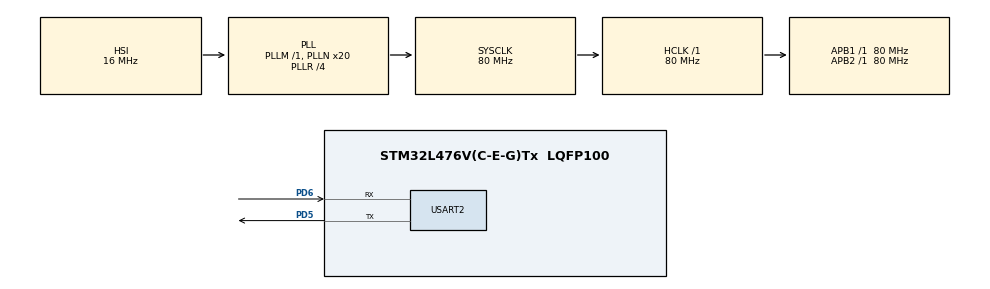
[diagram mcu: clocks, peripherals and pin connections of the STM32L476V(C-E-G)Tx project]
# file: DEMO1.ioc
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Mcu.Family=STM32L4
Mcu.Name=STM32L476V(C-E-G)Tx
Mcu.Package=LQFP100
NVIC.PriorityGroup=NVIC_PRIORITYGROUP_4
PD5.Mode=Asynchronous
PD5.Signal=USART2_TX
PD6.Mode=Asynchronous
PD6.Signal=USART2_RX
PH0-OSC_IN\ (PH0).Mode=HSE-External-Oscillator
PH0-OSC_IN\ (PH0).Signal=RCC_OSC_IN
PH1-OSC_OUT\ (PH1).Mode=HSE-External-Oscillator
PH1-OSC_OUT\ (PH1).Signal=RCC_OSC_OUT
ProjectManager.HeapSize=0x200
ProjectManager.StackSize=0x400
ProjectManager.TargetToolchain=SW4STM32
RCC.ADCFreq_Value=64000000
RCC.AHBFreq_Value=80000000
RCC.APB1Freq_Value=80000000
RCC.APB1TimFreq_Value=80000000
RCC.APB2Freq_Value=80000000
RCC.APB2TimFreq_Value=80000000
RCC.CortexFreq_Value=80000000
RCC.HCLKFreq_Value=80000000
RCC.HSE_VALUE=48000000
RCC.HSI_VALUE=16000000
RCC.LSE_VALUE=32768
RCC.MSI_VALUE=4000000
RCC.PLLN=20
RCC.PLLR=RCC_PLLR_DIV4
RCC.PLLSourceVirtual=RCC_PLLSOURCE_HSI
RCC.SYSCLKFreq_VALUE=80000000
RCC.SYSCLKSource=RCC_SYSCLKSOURCE_PLLCLK
RCC.USBFreq_Value=64000000
RCC.VCOOutputFreq_Value=320000000
USART2.VirtualMode-Asynchronous=VM_ASYNC
VP_CRC_VS_CRC.Mode=CRC_Activate
board=custom

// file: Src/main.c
/* USER CODE BEGIN Header */
/**
  ******************************************************************************
  * @file           : main.c
  * @brief          : Main program body
  ******************************************************************************
  * @attention
  *
  * <h2><center>&copy; Copyright (c) 2019 STMicroelectronics.
  * All rights reserved.</center></h2>
  *
  * This software component is licensed by ST under BSD 3-Clause license,
  * the "License"; You may not use this file except in compliance with the
  * License. You may obtain a copy of the License at:
  *                        opensource.org/licenses/BSD-3-Clause
  *
  ******************************************************************************
  */
/* USER CODE END Header */

#include "main.h"
#include "menu.h"
#include "string.h"
#include "cmac.h"
#include "KeyMng.h"
#include "common.h"

extern uint32_t _stext;
extern uint32_t _etext;
uint32_t length=0;
//uint32_t randomX = 0;

extern pFunction JumpToApplication;
extern uint32_t JumpAddress;

void SystemClock_Config(void);
static void MX_GPIO_Init(void);
static void MX_USART2_UART_Init(void);
static void MX_CRC_Init(void);
static void MX_RNG_Init(void);
unsigned char Key1[16];

int main(void)
{
	length = &_etext - &_stext;  //calculate size of .TEXT
	HAL_Init();
	SystemClock_Config();
	MX_GPIO_Init();
	MX_CRC_Init();

	/* USER CODE BEGIN 2 */
	MX_RNG_Init();
	MX_USART2_UART_Init();

	//randomX = HAL_RNG_GetRandomNumber(&hrng);

	FLASH_If_Init();
	Menu_Intro();

	Serial_PutString((uint8_t *)"\n\rBooting Program ......\r\n\n");
	for(int i = 0; i< 1000000; i++){}
	if(HAL_GPIO_ReadPin(GPIOA, GPIO_PIN_1) == 1)
	{
		Security_Access();
		Main_Menu();
	} else {
		KeyMng_ReadKey(3,(uint32_t*)Key1);
		if(Verify_MAC(Key1, (unsigned char *)0x08008020, 6240, (unsigned char *)0x08008000)){
			Serial_PutString((uint8_t *)"Program Verify SUCCESS !\r\n\n");
			Serial_PutString((uint8_t *)"Start program execution......\r\n\n");
			//Execute application
			SCB->VTOR = APPLICATION_ADDRESS+0x20;
			JumpAddress = *(__IO uint32_t*) (APPLICATION_ADDRESS + 4 + 0x20);
			JumpToApplication = (pFunction) JumpAddress;
			// Initialize user application's Stack Pointer
			__set_MSP(*(__IO uint32_t*) APPLICATION_ADDRESS +0x20);
			JumpToApplication();
		}
		else Serial_PutString((uint8_t *)"Program Verify FAIL !\r\n\n");
		Security_Access();
		Main_Menu();
	}

	while (1)
	{
	/* USER CODE END WHILE */

	}
}

void SystemClock_Config(void)
{
  RCC_OscInitTypeDef RCC_OscInitStruct = {0};
  RCC_ClkInitTypeDef RCC_ClkInitStruct = {0};
  RCC_PeriphCLKInitTypeDef PeriphClkInit = {0};

  /** Initializes the CPU, AHB and APB busses clocks
  */
  RCC_OscInitStruct.OscillatorType = RCC_OSCILLATORTYPE_HSI;
  RCC_OscInitStruct.HSIState = RCC_HSI_ON;
  RCC_OscInitStruct.HSICalibrationValue = RCC_HSICALIBRATION_DEFAULT;
  RCC_OscInitStruct.PLL.PLLState = RCC_PLL_ON;
  RCC_OscInitStruct.PLL.PLLSource = RCC_PLLSOURCE_HSI;
  RCC_OscInitStruct.PLL.PLLM = 1;
  RCC_OscInitStruct.PLL.PLLN = 20;
  RCC_OscInitStruct.PLL.PLLP = RCC_PLLP_DIV7;
  RCC_OscInitStruct.PLL.PLLQ = RCC_PLLQ_DIV8;
  RCC_OscInitStruct.PLL.PLLR = RCC_PLLR_DIV4;
  if (HAL_RCC_OscConfig(&RCC_OscInitStruct) != HAL_OK)
  {
    Error_Handler();
  }
  /** Initializes the CPU, AHB and APB busses clocks
  */
  RCC_ClkInitStruct.ClockType = RCC_CLOCKTYPE_HCLK|RCC_CLOCKTYPE_SYSCLK
                              |RCC_CLOCKTYPE_PCLK1|RCC_CLOCKTYPE_PCLK2;
  RCC_ClkInitStruct.SYSCLKSource = RCC_SYSCLKSOURCE_PLLCLK;
  RCC_ClkInitStruct.AHBCLKDivider = RCC_SYSCLK_DIV1;
  RCC_ClkInitStruct.APB1CLKDivider = RCC_HCLK_DIV1;
  RCC_ClkInitStruct.APB2CLKDivider = RCC_HCLK_DIV1;

  if (HAL_RCC_ClockConfig(&RCC_ClkInitStruct, FLASH_LATENCY_4) != HAL_OK)
  {
    Error_Handler();
  }
  PeriphClkInit.PeriphClockSelection = RCC_PERIPHCLK_USART2|RCC_PERIPHCLK_RNG;
  PeriphClkInit.Usart2ClockSelection = RCC_USART2CLKSOURCE_PCLK1;
  PeriphClkInit.RngClockSelection = RCC_RNGCLKSOURCE_PLL;
  if (HAL_RCCEx_PeriphCLKConfig(&PeriphClkInit) != HAL_OK)
  {
    Error_Handler();
  }
  /** Configure the main internal regulator output voltage
  */
  if (HAL_PWREx_ControlVoltageScaling(PWR_REGULATOR_VOLTAGE_SCALE1) != HAL_OK)
  {
    Error_Handler();
  }
}

static void MX_CRC_Init(void)
{

  hcrc.Instance = CRC;
  hcrc.Init.DefaultPolynomialUse = DEFAULT_INIT_VALUE_DISABLE;
  hcrc.Init.GeneratingPolynomial    = 0x1021;
  hcrc.Init.CRCLength               = CRC_POLYLENGTH_16B;

  hcrc.Init.DefaultInitValueUse = DEFAULT_INIT_VALUE_DISABLE;
  hcrc.Init.InitValue               = 0;

  hcrc.Init.InputDataInversionMode = CRC_INPUTDATA_INVERSION_NONE;
  hcrc.Init.OutputDataInversionMode = CRC_OUTPUTDATA_INVERSION_DISABLE;
  hcrc.InputDataFormat = CRC_INPUTDATA_FORMAT_BYTES;
  if (HAL_CRC_Init(&hcrc) != HAL_OK)
  {
    Error_Handler();
  }

}

static void MX_RNG_Init(void)
{

  hrng.Instance = RNG;
  if (HAL_RNG_Init(&hrng) != HAL_OK)
  {
    Error_Handler();
  }

}

static void MX_USART2_UART_Init(void)
{

  huart2.Instance = USART2;
  huart2.Init.BaudRate = 115200;
  huart2.Init.WordLength = UART_WORDLENGTH_8B;
  huart2.Init.StopBits = UART_STOPBITS_1;
  huart2.Init.Parity = UART_PARITY_NONE;
  huart2.Init.Mode = UART_MODE_TX_RX;
  huart2.Init.HwFlowCtl = UART_HWCONTROL_NONE;
  huart2.Init.OverSampling = UART_OVERSAMPLING_16;
  huart2.Init.OneBitSampling = UART_ONE_BIT_SAMPLE_DISABLE;
  huart2.AdvancedInit.AdvFeatureInit = UART_ADVFEATURE_NO_INIT;
  if (HAL_UART_Init(&huart2) != HAL_OK)
  {
    Error_Handler();
  }

}

static void MX_GPIO_Init(void)
{

  /* GPIO Ports Clock Enable */
  __HAL_RCC_GPIOH_CLK_ENABLE();
  __HAL_RCC_GPIOD_CLK_ENABLE();

  GPIO_InitTypeDef GPIO_InitStruct = {0};

    /* GPIO Ports Clock Enable */
    __HAL_RCC_GPIOA_CLK_ENABLE();

    /*Configure GPIO pins : PA1 PA2 PA3 PA5 */
    GPIO_InitStruct.Pin = GPIO_PIN_1|GPIO_PIN_2|GPIO_PIN_3|GPIO_PIN_5;
    GPIO_InitStruct.Mode = GPIO_MODE_INPUT;
    GPIO_InitStruct.Pull = GPIO_PULLDOWN;
    HAL_GPIO_Init(GPIOA, &GPIO_InitStruct);

}

void Error_Handler(void)
{
}

/************************ (C) COPYRIGHT STMicroelectronics *****END OF FILE****/
